One B-rep face of a CAD part: STEP entity #137.
In plain terms, the planar face has unit normal (0, -1, 0).
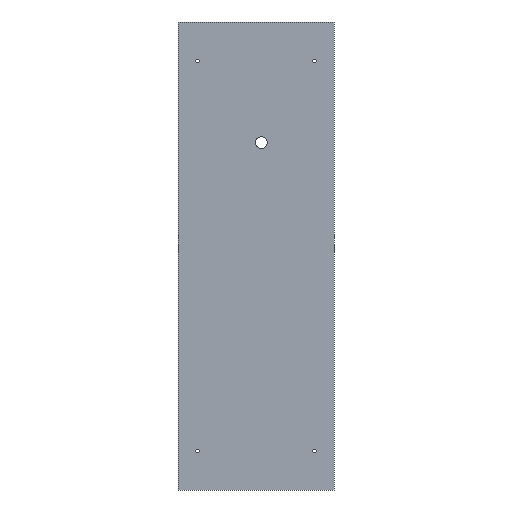
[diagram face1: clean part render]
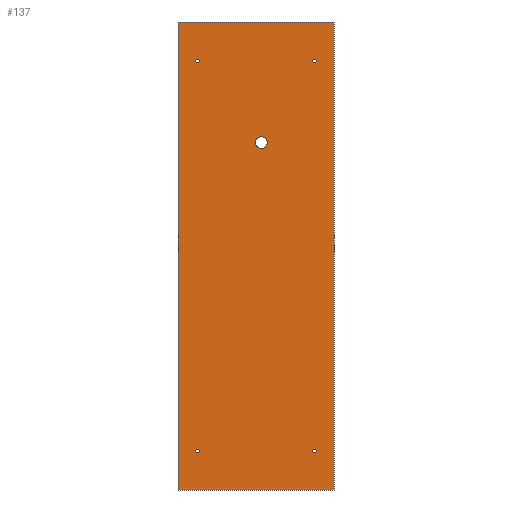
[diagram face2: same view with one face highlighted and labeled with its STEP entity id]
Its self-contained STEP definition (entity closure, numbers rounded to 3 decimals):
#21 = EDGE_CURVE('',#22,#24,#26,.T.);
#22 = VERTEX_POINT('',#23);
#23 = CARTESIAN_POINT('',(-100.,-52.,12.));
#24 = VERTEX_POINT('',#25);
#25 = CARTESIAN_POINT('',(-100.,-52.,612.));
#26 = SURFACE_CURVE('',#27,(#31,#43),.PCURVE_S1.);
#27 = LINE('',#28,#29);
#28 = CARTESIAN_POINT('',(-100.,-52.,12.));
#29 = VECTOR('',#30,1.);
#30 = DIRECTION('',(0.,0.,1.));
#31 = PCURVE('',#32,#37);
#32 = PLANE('',#33);
#33 = AXIS2_PLACEMENT_3D('',#34,#35,#36);
#34 = CARTESIAN_POINT('',(-100.,-52.,12.));
#35 = DIRECTION('',(1.,0.,0.));
#36 = DIRECTION('',(0.,0.,1.));
#37 = DEFINITIONAL_REPRESENTATION('',(#38),#42);
#38 = LINE('',#39,#40);
#39 = CARTESIAN_POINT('',(0.,0.));
#40 = VECTOR('',#41,1.);
#41 = DIRECTION('',(1.,0.));
#42 = ( GEOMETRIC_REPRESENTATION_CONTEXT(2) 
PARAMETRIC_REPRESENTATION_CONTEXT() REPRESENTATION_CONTEXT('2D SPACE',''
  ) );
#43 = PCURVE('',#44,#49);
#44 = PLANE('',#45);
#45 = AXIS2_PLACEMENT_3D('',#46,#47,#48);
#46 = CARTESIAN_POINT('',(-100.,-52.,12.));
#47 = DIRECTION('',(0.,1.,0.));
#48 = DIRECTION('',(0.,0.,1.));
#49 = DEFINITIONAL_REPRESENTATION('',(#50),#54);
#50 = LINE('',#51,#52);
#51 = CARTESIAN_POINT('',(0.,0.));
#52 = VECTOR('',#53,1.);
#53 = DIRECTION('',(1.,0.));
#54 = ( GEOMETRIC_REPRESENTATION_CONTEXT(2) 
PARAMETRIC_REPRESENTATION_CONTEXT() REPRESENTATION_CONTEXT('2D SPACE',''
  ) );
#72 = PLANE('',#73);
#73 = AXIS2_PLACEMENT_3D('',#74,#75,#76);
#74 = CARTESIAN_POINT('',(-100.,-52.,12.));
#75 = DIRECTION('',(0.,0.,1.));
#76 = DIRECTION('',(1.,0.,0.));
#126 = PLANE('',#127);
#127 = AXIS2_PLACEMENT_3D('',#128,#129,#130);
#128 = CARTESIAN_POINT('',(-100.,-52.,612.));
#129 = DIRECTION('',(0.,0.,1.));
#130 = DIRECTION('',(1.,0.,0.));
#137 = ADVANCED_FACE('',(#138,#213,#244,#275,#306,#337),#44,.F.);
#138 = FACE_BOUND('',#139,.F.);
#139 = EDGE_LOOP('',(#140,#163,#164,#187));
#140 = ORIENTED_EDGE('',*,*,#141,.F.);
#141 = EDGE_CURVE('',#22,#142,#144,.T.);
#142 = VERTEX_POINT('',#143);
#143 = CARTESIAN_POINT('',(100.,-52.,12.));
#144 = SURFACE_CURVE('',#145,(#149,#156),.PCURVE_S1.);
#145 = LINE('',#146,#147);
#146 = CARTESIAN_POINT('',(-100.,-52.,12.));
#147 = VECTOR('',#148,1.);
#148 = DIRECTION('',(1.,0.,0.));
#149 = PCURVE('',#44,#150);
#150 = DEFINITIONAL_REPRESENTATION('',(#151),#155);
#151 = LINE('',#152,#153);
#152 = CARTESIAN_POINT('',(0.,0.));
#153 = VECTOR('',#154,1.);
#154 = DIRECTION('',(0.,1.));
#155 = ( GEOMETRIC_REPRESENTATION_CONTEXT(2) 
PARAMETRIC_REPRESENTATION_CONTEXT() REPRESENTATION_CONTEXT('2D SPACE',''
  ) );
#156 = PCURVE('',#72,#157);
#157 = DEFINITIONAL_REPRESENTATION('',(#158),#162);
#158 = LINE('',#159,#160);
#159 = CARTESIAN_POINT('',(0.,0.));
#160 = VECTOR('',#161,1.);
#161 = DIRECTION('',(1.,0.));
#162 = ( GEOMETRIC_REPRESENTATION_CONTEXT(2) 
PARAMETRIC_REPRESENTATION_CONTEXT() REPRESENTATION_CONTEXT('2D SPACE',''
  ) );
#163 = ORIENTED_EDGE('',*,*,#21,.T.);
#164 = ORIENTED_EDGE('',*,*,#165,.T.);
#165 = EDGE_CURVE('',#24,#166,#168,.T.);
#166 = VERTEX_POINT('',#167);
#167 = CARTESIAN_POINT('',(100.,-52.,612.));
#168 = SURFACE_CURVE('',#169,(#173,#180),.PCURVE_S1.);
#169 = LINE('',#170,#171);
#170 = CARTESIAN_POINT('',(-100.,-52.,612.));
#171 = VECTOR('',#172,1.);
#172 = DIRECTION('',(1.,0.,0.));
#173 = PCURVE('',#44,#174);
#174 = DEFINITIONAL_REPRESENTATION('',(#175),#179);
#175 = LINE('',#176,#177);
#176 = CARTESIAN_POINT('',(600.,0.));
#177 = VECTOR('',#178,1.);
#178 = DIRECTION('',(0.,1.));
#179 = ( GEOMETRIC_REPRESENTATION_CONTEXT(2) 
PARAMETRIC_REPRESENTATION_CONTEXT() REPRESENTATION_CONTEXT('2D SPACE',''
  ) );
#180 = PCURVE('',#126,#181);
#181 = DEFINITIONAL_REPRESENTATION('',(#182),#186);
#182 = LINE('',#183,#184);
#183 = CARTESIAN_POINT('',(0.,0.));
#184 = VECTOR('',#185,1.);
#185 = DIRECTION('',(1.,0.));
#186 = ( GEOMETRIC_REPRESENTATION_CONTEXT(2) 
PARAMETRIC_REPRESENTATION_CONTEXT() REPRESENTATION_CONTEXT('2D SPACE',''
  ) );
#187 = ORIENTED_EDGE('',*,*,#188,.F.);
#188 = EDGE_CURVE('',#142,#166,#189,.T.);
#189 = SURFACE_CURVE('',#190,(#194,#201),.PCURVE_S1.);
#190 = LINE('',#191,#192);
#191 = CARTESIAN_POINT('',(100.,-52.,12.));
#192 = VECTOR('',#193,1.);
#193 = DIRECTION('',(0.,0.,1.));
#194 = PCURVE('',#44,#195);
#195 = DEFINITIONAL_REPRESENTATION('',(#196),#200);
#196 = LINE('',#197,#198);
#197 = CARTESIAN_POINT('',(0.,200.));
#198 = VECTOR('',#199,1.);
#199 = DIRECTION('',(1.,0.));
#200 = ( GEOMETRIC_REPRESENTATION_CONTEXT(2) 
PARAMETRIC_REPRESENTATION_CONTEXT() REPRESENTATION_CONTEXT('2D SPACE',''
  ) );
#201 = PCURVE('',#202,#207);
#202 = PLANE('',#203);
#203 = AXIS2_PLACEMENT_3D('',#204,#205,#206);
#204 = CARTESIAN_POINT('',(100.,-52.,12.));
#205 = DIRECTION('',(1.,0.,0.));
#206 = DIRECTION('',(0.,0.,1.));
#207 = DEFINITIONAL_REPRESENTATION('',(#208),#212);
#208 = LINE('',#209,#210);
#209 = CARTESIAN_POINT('',(0.,0.));
#210 = VECTOR('',#211,1.);
#211 = DIRECTION('',(1.,0.));
#212 = ( GEOMETRIC_REPRESENTATION_CONTEXT(2) 
PARAMETRIC_REPRESENTATION_CONTEXT() REPRESENTATION_CONTEXT('2D SPACE',''
  ) );
#213 = FACE_BOUND('',#214,.F.);
#214 = EDGE_LOOP('',(#215));
#215 = ORIENTED_EDGE('',*,*,#216,.F.);
#216 = EDGE_CURVE('',#217,#217,#219,.T.);
#217 = VERTEX_POINT('',#218);
#218 = CARTESIAN_POINT('',(-75.,-52.,64.25));
#219 = SURFACE_CURVE('',#220,(#225,#232),.PCURVE_S1.);
#220 = CIRCLE('',#221,2.25);
#221 = AXIS2_PLACEMENT_3D('',#222,#223,#224);
#222 = CARTESIAN_POINT('',(-75.,-52.,62.));
#223 = DIRECTION('',(0.,1.,0.));
#224 = DIRECTION('',(0.,-0.,1.));
#225 = PCURVE('',#44,#226);
#226 = DEFINITIONAL_REPRESENTATION('',(#227),#231);
#227 = CIRCLE('',#228,2.25);
#228 = AXIS2_PLACEMENT_2D('',#229,#230);
#229 = CARTESIAN_POINT('',(50.,25.));
#230 = DIRECTION('',(1.,0.));
#231 = ( GEOMETRIC_REPRESENTATION_CONTEXT(2) 
PARAMETRIC_REPRESENTATION_CONTEXT() REPRESENTATION_CONTEXT('2D SPACE',''
  ) );
#232 = PCURVE('',#233,#238);
#233 = CYLINDRICAL_SURFACE('',#234,2.25);
#234 = AXIS2_PLACEMENT_3D('',#235,#236,#237);
#235 = CARTESIAN_POINT('',(-75.,-52.,62.));
#236 = DIRECTION('',(0.,1.,0.));
#237 = DIRECTION('',(0.,-0.,1.));
#238 = DEFINITIONAL_REPRESENTATION('',(#239),#243);
#239 = LINE('',#240,#241);
#240 = CARTESIAN_POINT('',(0.,0.));
#241 = VECTOR('',#242,1.);
#242 = DIRECTION('',(1.,0.));
#243 = ( GEOMETRIC_REPRESENTATION_CONTEXT(2) 
PARAMETRIC_REPRESENTATION_CONTEXT() REPRESENTATION_CONTEXT('2D SPACE',''
  ) );
#244 = FACE_BOUND('',#245,.F.);
#245 = EDGE_LOOP('',(#246));
#246 = ORIENTED_EDGE('',*,*,#247,.F.);
#247 = EDGE_CURVE('',#248,#248,#250,.T.);
#248 = VERTEX_POINT('',#249);
#249 = CARTESIAN_POINT('',(-75.,-52.,564.25));
#250 = SURFACE_CURVE('',#251,(#256,#263),.PCURVE_S1.);
#251 = CIRCLE('',#252,2.25);
#252 = AXIS2_PLACEMENT_3D('',#253,#254,#255);
#253 = CARTESIAN_POINT('',(-75.,-52.,562.));
#254 = DIRECTION('',(0.,1.,0.));
#255 = DIRECTION('',(0.,-0.,1.));
#256 = PCURVE('',#44,#257);
#257 = DEFINITIONAL_REPRESENTATION('',(#258),#262);
#258 = CIRCLE('',#259,2.25);
#259 = AXIS2_PLACEMENT_2D('',#260,#261);
#260 = CARTESIAN_POINT('',(550.,25.));
#261 = DIRECTION('',(1.,0.));
#262 = ( GEOMETRIC_REPRESENTATION_CONTEXT(2) 
PARAMETRIC_REPRESENTATION_CONTEXT() REPRESENTATION_CONTEXT('2D SPACE',''
  ) );
#263 = PCURVE('',#264,#269);
#264 = CYLINDRICAL_SURFACE('',#265,2.25);
#265 = AXIS2_PLACEMENT_3D('',#266,#267,#268);
#266 = CARTESIAN_POINT('',(-75.,-52.,562.));
#267 = DIRECTION('',(0.,1.,0.));
#268 = DIRECTION('',(0.,-0.,1.));
#269 = DEFINITIONAL_REPRESENTATION('',(#270),#274);
#270 = LINE('',#271,#272);
#271 = CARTESIAN_POINT('',(0.,0.));
#272 = VECTOR('',#273,1.);
#273 = DIRECTION('',(1.,0.));
#274 = ( GEOMETRIC_REPRESENTATION_CONTEXT(2) 
PARAMETRIC_REPRESENTATION_CONTEXT() REPRESENTATION_CONTEXT('2D SPACE',''
  ) );
#275 = FACE_BOUND('',#276,.F.);
#276 = EDGE_LOOP('',(#277));
#277 = ORIENTED_EDGE('',*,*,#278,.F.);
#278 = EDGE_CURVE('',#279,#279,#281,.T.);
#279 = VERTEX_POINT('',#280);
#280 = CARTESIAN_POINT('',(75.,-52.,64.25));
#281 = SURFACE_CURVE('',#282,(#287,#294),.PCURVE_S1.);
#282 = CIRCLE('',#283,2.25);
#283 = AXIS2_PLACEMENT_3D('',#284,#285,#286);
#284 = CARTESIAN_POINT('',(75.,-52.,62.));
#285 = DIRECTION('',(0.,1.,0.));
#286 = DIRECTION('',(0.,-0.,1.));
#287 = PCURVE('',#44,#288);
#288 = DEFINITIONAL_REPRESENTATION('',(#289),#293);
#289 = CIRCLE('',#290,2.25);
#290 = AXIS2_PLACEMENT_2D('',#291,#292);
#291 = CARTESIAN_POINT('',(50.,175.));
#292 = DIRECTION('',(1.,0.));
#293 = ( GEOMETRIC_REPRESENTATION_CONTEXT(2) 
PARAMETRIC_REPRESENTATION_CONTEXT() REPRESENTATION_CONTEXT('2D SPACE',''
  ) );
#294 = PCURVE('',#295,#300);
#295 = CYLINDRICAL_SURFACE('',#296,2.25);
#296 = AXIS2_PLACEMENT_3D('',#297,#298,#299);
#297 = CARTESIAN_POINT('',(75.,-52.,62.));
#298 = DIRECTION('',(0.,1.,0.));
#299 = DIRECTION('',(0.,-0.,1.));
#300 = DEFINITIONAL_REPRESENTATION('',(#301),#305);
#301 = LINE('',#302,#303);
#302 = CARTESIAN_POINT('',(0.,0.));
#303 = VECTOR('',#304,1.);
#304 = DIRECTION('',(1.,0.));
#305 = ( GEOMETRIC_REPRESENTATION_CONTEXT(2) 
PARAMETRIC_REPRESENTATION_CONTEXT() REPRESENTATION_CONTEXT('2D SPACE',''
  ) );
#306 = FACE_BOUND('',#307,.F.);
#307 = EDGE_LOOP('',(#308));
#308 = ORIENTED_EDGE('',*,*,#309,.F.);
#309 = EDGE_CURVE('',#310,#310,#312,.T.);
#310 = VERTEX_POINT('',#311);
#311 = CARTESIAN_POINT('',(7.,-52.,465.));
#312 = SURFACE_CURVE('',#313,(#318,#325),.PCURVE_S1.);
#313 = CIRCLE('',#314,7.5);
#314 = AXIS2_PLACEMENT_3D('',#315,#316,#317);
#315 = CARTESIAN_POINT('',(7.,-52.,457.5));
#316 = DIRECTION('',(0.,1.,0.));
#317 = DIRECTION('',(0.,-0.,1.));
#318 = PCURVE('',#44,#319);
#319 = DEFINITIONAL_REPRESENTATION('',(#320),#324);
#320 = CIRCLE('',#321,7.5);
#321 = AXIS2_PLACEMENT_2D('',#322,#323);
#322 = CARTESIAN_POINT('',(445.5,107.));
#323 = DIRECTION('',(1.,0.));
#324 = ( GEOMETRIC_REPRESENTATION_CONTEXT(2) 
PARAMETRIC_REPRESENTATION_CONTEXT() REPRESENTATION_CONTEXT('2D SPACE',''
  ) );
#325 = PCURVE('',#326,#331);
#326 = CYLINDRICAL_SURFACE('',#327,7.5);
#327 = AXIS2_PLACEMENT_3D('',#328,#329,#330);
#328 = CARTESIAN_POINT('',(7.,-52.,457.5));
#329 = DIRECTION('',(0.,1.,0.));
#330 = DIRECTION('',(0.,-0.,1.));
#331 = DEFINITIONAL_REPRESENTATION('',(#332),#336);
#332 = LINE('',#333,#334);
#333 = CARTESIAN_POINT('',(0.,0.));
#334 = VECTOR('',#335,1.);
#335 = DIRECTION('',(1.,0.));
#336 = ( GEOMETRIC_REPRESENTATION_CONTEXT(2) 
PARAMETRIC_REPRESENTATION_CONTEXT() REPRESENTATION_CONTEXT('2D SPACE',''
  ) );
#337 = FACE_BOUND('',#338,.F.);
#338 = EDGE_LOOP('',(#339));
#339 = ORIENTED_EDGE('',*,*,#340,.F.);
#340 = EDGE_CURVE('',#341,#341,#343,.T.);
#341 = VERTEX_POINT('',#342);
#342 = CARTESIAN_POINT('',(75.,-52.,564.25));
#343 = SURFACE_CURVE('',#344,(#349,#356),.PCURVE_S1.);
#344 = CIRCLE('',#345,2.25);
#345 = AXIS2_PLACEMENT_3D('',#346,#347,#348);
#346 = CARTESIAN_POINT('',(75.,-52.,562.));
#347 = DIRECTION('',(0.,1.,0.));
#348 = DIRECTION('',(0.,-0.,1.));
#349 = PCURVE('',#44,#350);
#350 = DEFINITIONAL_REPRESENTATION('',(#351),#355);
#351 = CIRCLE('',#352,2.25);
#352 = AXIS2_PLACEMENT_2D('',#353,#354);
#353 = CARTESIAN_POINT('',(550.,175.));
#354 = DIRECTION('',(1.,0.));
#355 = ( GEOMETRIC_REPRESENTATION_CONTEXT(2) 
PARAMETRIC_REPRESENTATION_CONTEXT() REPRESENTATION_CONTEXT('2D SPACE',''
  ) );
#356 = PCURVE('',#357,#362);
#357 = CYLINDRICAL_SURFACE('',#358,2.25);
#358 = AXIS2_PLACEMENT_3D('',#359,#360,#361);
#359 = CARTESIAN_POINT('',(75.,-52.,562.));
#360 = DIRECTION('',(0.,1.,0.));
#361 = DIRECTION('',(0.,-0.,1.));
#362 = DEFINITIONAL_REPRESENTATION('',(#363),#367);
#363 = LINE('',#364,#365);
#364 = CARTESIAN_POINT('',(0.,0.));
#365 = VECTOR('',#366,1.);
#366 = DIRECTION('',(1.,0.));
#367 = ( GEOMETRIC_REPRESENTATION_CONTEXT(2) 
PARAMETRIC_REPRESENTATION_CONTEXT() REPRESENTATION_CONTEXT('2D SPACE',''
  ) );
